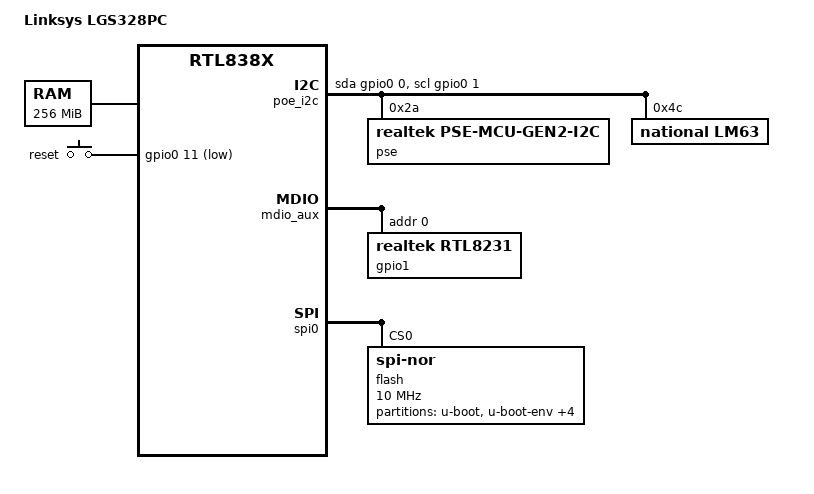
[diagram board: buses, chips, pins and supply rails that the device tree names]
// SPDX-License-Identifier: GPL-2.0-or-later OR MIT

/*
 * Linksys LGS328PC
 *
 * Hardware revision:
 *   U-Boot magic_number: 0x60401070
 *   SoC:                 RTL8382M
 *   Copper PHYs:         RTL8218B / internal RTL8218B / RTL8218B
 *   PoE MCU:             Gen2 Realtek PSE protocol device at 0x2a
 *                        (kernel reports GD32F230; OEM bootloader labels
 *                         its PoE MCU as Nuvoton M0516LDE)
 *   PSE silicon:         3 x RTL8238B, 24 ports total
 *
 * This DTS is based on current OpenWrt main:
 *   - rtl8380_linksys_lgs310c.dts for Linksys flash/NVMEM conventions
 *   - rtl8382_d-link_dgs-1210-28_common.dtsi for the RTL8382 copper
 *     PHY/SerDes topology
 *
 * Additional board details below were recovered from the original
 * LGS328PC v1.01.02.02 firmware:
 *
 *   SoC GPIO 0:  PoE MCU raw-I2C SDA
 *   SoC GPIO 1:  PoE MCU raw-I2C SCL
 *   SoC GPIO 11: reset button, active low
 *   SoC GPIO 12: board LED output (exact front-panel function TBD)
 *   SoC GPIO 13: LED-mode button, active low (not registered yet;
 *                 gpio_button_hotplug rejects KEY_PROG1)
 *
 *   RTL8231 GPIO 1: PoE control line; OEM firmware drives it high
 *                   before accessing the PoE MCU. OpenWrt therefore
 *                   keeps this line asserted high with a GPIO hog.
 *   RTL8231 GPIO 5: fan-fault input
 *
 *   PoE MCU raw-I2C address: 0x2a
 *   LM63 fan/temperature monitor address: 0x4c
 *
 * Live OpenWrt i2cdetect confirms devices at 0x2a and 0x4c.
 *
 * PSE PI mapping:
 *   The OEM image contains two different 24-entry RTL8238B maps:
 *     - MCU-port map:     3,2,1,0,7,6,5,4,...
 *     - logical-port map: 0,1,2,3,4,5,6,7,...
 *
 *   Linux realtek-pse-mcu sends the PSE PI id directly as the MCU logical
 *   port id. Live hardware testing confirmed that PI7 powers front-panel
 *   port 8. Therefore DSA logical port N maps directly to PSE PI N-1.
 *
 * SFP ports 25..28 are intentionally omitted until they can be tested.
 */

#include <dt-bindings/gpio/gpio.h>
#include <dt-bindings/input/input.h>

#include "rtl838x.dtsi"

/ {
	compatible = "linksys,lgs328pc", "realtek,rtl838x-soc";
	model = "Linksys LGS328PC";

	aliases {
		label-mac-device = &ethernet0;
	};

	memory@0 {
		device_type = "memory";
		reg = <0x0 0x10000000>;
	};

	keys {
		compatible = "gpio-keys";

		reset {
			label = "reset";
			gpios = <&gpio0 11 GPIO_ACTIVE_LOW>;
			linux,code = <KEY_RESTART>;
		};

	};

	/*
	 * The OEM SDK configures SMI group 6 as a GPIO-bitbanged bus:
	 *   SDA: SoC GPIO 0
	 *   SCL: SoC GPIO 1
	 *
	 * The bus carries both the Nuvoton/RTL8238B PoE interface at 0x2a
	 * and the LM63 hardware monitor at 0x4c. The OEM PoE accessors use
	 * raw byte reads/writes rather than SMBus framing, matching
	 * realtek,pse-mcu-gen2-i2c.
	 *
	 * No explicit i2c-gpio delay is specified. The OEM SDK's
	 * B2B-delay value is an inter-message delay and should not be
	 * translated into an I2C clock period.
	 */
	poe_i2c: i2c-gpio-poe {
		compatible = "i2c-gpio";

		sda-gpios = <&gpio0 0
			(GPIO_ACTIVE_HIGH | GPIO_OPEN_DRAIN)>;
		scl-gpios = <&gpio0 1
			(GPIO_ACTIVE_HIGH | GPIO_OPEN_DRAIN)>;

		#address-cells = <1>;
		#size-cells = <0>;

		pse: ethernet-pse@2a {
			compatible = "realtek,pse-mcu-gen2-i2c";
			reg = <0x2a>;

			pse-pis {
				#address-cells = <1>;
				#size-cells = <0>;

				PSE_PI(0)
				PSE_PI(1)
				PSE_PI(2)
				PSE_PI(3)
				PSE_PI(4)
				PSE_PI(5)
				PSE_PI(6)
				PSE_PI(7)
				PSE_PI(8)
				PSE_PI(9)
				PSE_PI(10)
				PSE_PI(11)
				PSE_PI(12)
				PSE_PI(13)
				PSE_PI(14)
				PSE_PI(15)
				PSE_PI(16)
				PSE_PI(17)
				PSE_PI(18)
				PSE_PI(19)
				PSE_PI(20)
				PSE_PI(21)
				PSE_PI(22)
				PSE_PI(23)
			};
		};

		/*
		 * National Semiconductor LM63 hardware monitor.
		 * Live I2C scan confirms address 0x4c.
		 *
		 * OEM firmware programs the LM63 at runtime with:
		 *   4d=1f  PWM divider
		 *   4f=0b  LUT hysteresis (11 C)
		 *   50=0b  LUT point 1 temperature (11 C)
		 *   51=1f  LUT point 1 PWM (50%)
		 *   52=37  LUT point 2 temperature (55 C)
		 *   53=3e  LUT point 2 PWM (100%)
		 *   4a=0a  automatic LUT mode, slow PWM master clock
		 *
		 * The upstream LM63 binding has no DT properties for this LUT;
		 * board fan policy therefore needs to be applied at runtime.
		 */
		lm63@4c {
			compatible = "national,lm63";
			reg = <0x4c>;
		};
	};
};

/*
 * Names recovered from the OEM board-support routines.
 * Unnamed GPIOs are deliberately left blank.
 */
&gpio0 {
	gpio-line-names =
		"poe-sda",		/* 0 */
		"poe-scl",		/* 1 */
		"",			/* 2 */
		"",			/* 3 */
		"",			/* 4 */
		"",			/* 5 */
		"",			/* 6 */
		"",			/* 7 */
		"",			/* 8 */
		"",			/* 9 */
		"",			/* 10 */
		"reset",		/* 11 */
		"board-led",		/* 12: exact function TBD */
		"led-mode";		/* 13 */
};

&ethernet0 {
	nvmem-cells = <&macaddr_ubootenv_ethaddr 0>;
	nvmem-cell-names = "mac-address";
};

&mdio_aux {
	status = "okay";

	gpio1: expander@0 {
		compatible = "realtek,rtl8231";
		reg = <0>;

		gpio-controller;
		#gpio-cells = <2>;
		gpio-ranges = <&gpio1 0 0 37>;

		gpio-line-names =
			"",			/* 0 */
			"poe-control",		/* 1 */
			"",			/* 2 */
			"",			/* 3 */
			"",			/* 4 */
			"fan-fault";		/* 5 */

		/*
		 * The OEM EGS7228P board initialization drives RTL8231 GPIO 1
		 * high before accessing the PoE MCU. Keep it asserted from
		 * GPIO-controller probe onward. Exact electrical semantics
		 * (enable/reset-release/gate) can be named more precisely once
		 * confirmed, but the required level is known.
		 */
		poe-control-hog {
			gpio-hog;
			gpios = <1 GPIO_ACTIVE_HIGH>;
			output-high;
			line-name = "poe-control";
		};

		led-controller {
			compatible = "realtek,rtl8231-leds";
			status = "disabled";
		};
	};
};

&spi0 {
	status = "okay";

	flash@0 {
		compatible = "jedec,spi-nor";
		reg = <0>;
		spi-max-frequency = <10000000>;

		partitions {
			compatible = "fixed-partitions";
			#address-cells = <1>;
			#size-cells = <1>;

			partition@0 {
				label = "u-boot";
				reg = <0x00000000 0x00080000>;
				read-only;
			};

			partition@80000 {
				label = "u-boot-env";
				reg = <0x00080000 0x00010000>;

				nvmem-layout {
					compatible = "u-boot,env";

					macaddr_ubootenv_ethaddr: ethaddr {
						#nvmem-cell-cells = <1>;
					};
				};
			};

			partition@90000 {
				label = "u-boot-env2";
				reg = <0x00090000 0x00010000>;
			};

			partition@a0000 {
				label = "jffs2";
				reg = <0x000a0000 0x00500000>;
			};

			partition@5a0000 {
				label = "firmware";
				compatible = "openwrt,uimage";
				reg = <0x005a0000 0x00d30000>;
			};

			partition@12d0000 {
				label = "kernel2";
				reg = <0x012d0000 0x00d30000>;
			};
		};
	};
};

/*
 * RTL8382M_8218B_INTPHY_8218B_8214FC
 *
 * Only the 24 copper ports are described here:
 *   MAC  0..7:  external RTL8218B
 *   MAC  8..15: RTL8382 internal PHYs
 *   MAC 16..23: external RTL8218B
 *
 * MAC 24..27 / RTL8214FC / SFP cages are intentionally omitted.
 */
&mdio_bus0 {
	PHY_C22(0, 0)
	PHY_C22(1, 1)
	PHY_C22(2, 2)
	PHY_C22(3, 3)
	PHY_C22(4, 4)
	PHY_C22(5, 5)
	PHY_C22(6, 6)
	PHY_C22(7, 7)

	PHY_C22(8, 8)
	PHY_C22(9, 9)
	PHY_C22(10, 10)
	PHY_C22(11, 11)
	PHY_C22(12, 12)
	PHY_C22(13, 13)
	PHY_C22(14, 14)
	PHY_C22(15, 15)

	PHY_C22(16, 16)
	PHY_C22(17, 17)
	PHY_C22(18, 18)
	PHY_C22(19, 19)
	PHY_C22(20, 20)
	PHY_C22(21, 21)
	PHY_C22(22, 22)
	PHY_C22(23, 23)
};

/*
 * Linux PSE PI ids are the MCU logical port ids.
 * Live test: assigning lan5 to PI7 powered physical port 8, proving the
 * previous reversed-by-four DT mapping was wrong. Use the OEM logical map:
 * front-panel port 1..24 -> PI 0..23.
 */
&phy0  { pses = <&pse_pi0>; };
&phy1  { pses = <&pse_pi1>; };
&phy2  { pses = <&pse_pi2>; };
&phy3  { pses = <&pse_pi3>; };

&phy4  { pses = <&pse_pi4>; };
&phy5  { pses = <&pse_pi5>; };
&phy6  { pses = <&pse_pi6>; };
&phy7  { pses = <&pse_pi7>; };

&phy8  { pses = <&pse_pi8>; };
&phy9  { pses = <&pse_pi9>; };
&phy10 { pses = <&pse_pi10>; };
&phy11 { pses = <&pse_pi11>; };

&phy12 { pses = <&pse_pi12>; };
&phy13 { pses = <&pse_pi13>; };
&phy14 { pses = <&pse_pi14>; };
&phy15 { pses = <&pse_pi15>; };

&phy16 { pses = <&pse_pi16>; };
&phy17 { pses = <&pse_pi17>; };
&phy18 { pses = <&pse_pi18>; };
&phy19 { pses = <&pse_pi19>; };

&phy20 { pses = <&pse_pi20>; };
&phy21 { pses = <&pse_pi21>; };
&phy22 { pses = <&pse_pi22>; };
&phy23 { pses = <&pse_pi23>; };

&switch0 {
	ethernet-ports {
		#address-cells = <1>;
		#size-cells = <0>;

		SWITCH_PORT_SDS(0, 1, 0, 0, qsgmii)
		SWITCH_PORT_SDS(1, 2, 0, 1, qsgmii)
		SWITCH_PORT_SDS(2, 3, 0, 2, qsgmii)
		SWITCH_PORT_SDS(3, 4, 0, 3, qsgmii)
		SWITCH_PORT_SDS(4, 5, 1, 0, qsgmii)
		SWITCH_PORT_SDS(5, 6, 1, 1, qsgmii)
		SWITCH_PORT_SDS(6, 7, 1, 2, qsgmii)
		SWITCH_PORT_SDS(7, 8, 1, 3, qsgmii)

		SWITCH_PORT(8, 9, internal)
		SWITCH_PORT(9, 10, internal)
		SWITCH_PORT(10, 11, internal)
		SWITCH_PORT(11, 12, internal)
		SWITCH_PORT(12, 13, internal)
		SWITCH_PORT(13, 14, internal)
		SWITCH_PORT(14, 15, internal)
		SWITCH_PORT(15, 16, internal)

		SWITCH_PORT_SDS(16, 17, 2, 0, qsgmii)
		SWITCH_PORT_SDS(17, 18, 2, 1, qsgmii)
		SWITCH_PORT_SDS(18, 19, 2, 2, qsgmii)
		SWITCH_PORT_SDS(19, 20, 2, 3, qsgmii)
		SWITCH_PORT_SDS(20, 21, 3, 0, qsgmii)
		SWITCH_PORT_SDS(21, 22, 3, 1, qsgmii)
		SWITCH_PORT_SDS(22, 23, 3, 2, qsgmii)
		SWITCH_PORT_SDS(23, 24, 3, 3, qsgmii)

		port@28 {
			ethernet = <&ethernet0>;
			reg = <28>;
			phy-mode = "internal";

			fixed-link {
				speed = <1000>;
				full-duplex;
			};
		};
	};
};
